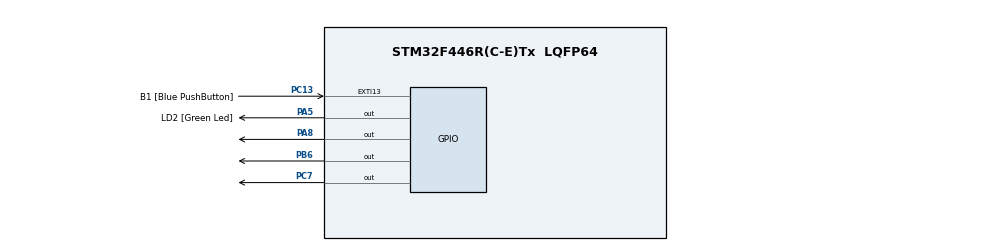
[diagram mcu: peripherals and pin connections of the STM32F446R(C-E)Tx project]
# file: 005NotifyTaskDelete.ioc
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Mcu.Family=STM32F4
Mcu.Name=STM32F446R(C-E)Tx
Mcu.Package=LQFP64
NVIC.PriorityGroup=NVIC_PRIORITYGROUP_4
NVIC.TIM5_IRQn=true\:0\:0\:false\:false\:true\:false\:true
NVIC.TimeBase=TIM5_IRQn
NVIC.TimeBaseIP=TIM5
PA13.GPIO_Label=TMS
PA13.Signal=SYS_JTMS-SWDIO
PA14.GPIO_Label=TCK
PA14.Signal=SYS_JTCK-SWCLK
PA2.GPIO_Label=USART_TX
PA2.Signal=USART2_TX
PA3.GPIO_Label=USART_RX
PA3.Signal=USART2_RX
PA5.GPIO_Label=LD2 [Green Led]
PA5.Signal=GPIO_Output
PA8.Signal=GPIO_Output
PB3.GPIO_Label=SWO
PB3.Signal=SYS_JTDO-SWO
PB6.Signal=GPIO_Output
PC13.GPIO_Label=B1 [Blue PushButton]
PC13.GPIO_ModeDefaultEXTI=GPIO_MODE_IT_FALLING
PC13.Signal=GPXTI13
PC14-OSC32_IN.Signal=RCC_OSC32_IN
PC15-OSC32_OUT.Signal=RCC_OSC32_OUT
PC7.Signal=GPIO_Output
PH0-OSC_IN.Signal=RCC_OSC_IN
PH1-OSC_OUT.Signal=RCC_OSC_OUT
ProjectManager.HeapSize=0x200
ProjectManager.StackSize=0x400
ProjectManager.TargetToolchain=STM32CubeIDE
RCC.AHBFreq_Value=84000000
RCC.APB1CLKDivider=RCC_HCLK_DIV2
RCC.APB1Freq_Value=42000000
RCC.APB1TimFreq_Value=84000000
RCC.APB2Freq_Value=84000000
RCC.APB2TimFreq_Value=84000000
RCC.CortexFreq_Value=84000000
RCC.FLatency-AdvancedSettings=FLASH_LATENCY_2
RCC.HCLKFreq_Value=84000000
RCC.HSE_VALUE=8000000
RCC.HSI_VALUE=16000000
RCC.LSE_VALUE=32768
RCC.PLLN=336
RCC.PLLP=RCC_PLLP_DIV4
RCC.SYSCLKFreq_VALUE=84000000
RCC.SYSCLKSource=RCC_SYSCLKSOURCE_PLLCLK
RCC.USBFreq_Value=168000000
RCC.VCOOutputFreq_Value=336000000
VP_SYS_VS_tim5.Mode=TIM5
board=NUCLEO-F446RE

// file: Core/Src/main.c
/* USER CODE BEGIN Header */
/**
  ******************************************************************************
  * @file           : main.c
  * @brief          : Main program body
  ******************************************************************************
  * @attention
  *
  * <h2><center>&copy; Copyright (c) 2022 STMicroelectronics.
  * All rights reserved.</center></h2>
  *
  * This software component is licensed by ST under BSD 3-Clause license,
  * the "License"; You may not use this file except in compliance with the
  * License. You may obtain a copy of the License at:
  *                        opensource.org/licenses/BSD-3-Clause
  *
  ******************************************************************************
  */
/* USER CODE END Header */

#include "main.h"

/* USER CODE BEGIN Includes */
#include "FreeRTOS.h"
#include "task.h"
/* USER CODE END Includes */

/* USER CODE BEGIN PV */
#define DWT_CTRL (*(volatile uint32_t*)0xE0001000)
/* USER CODE END PV */

void SystemClock_Config(void);
static void MX_GPIO_Init(void);
/* USER CODE BEGIN PFP */
void LedRedTask(void *parameter);
void LedGreenTask(void *parameter);
void LedYellowTask(void *parameter);
static void ButtonTask(void *parameter);
extern void SEGGER_UART_init(U32 baud);
/* USER CODE END PFP */

/* USER CODE BEGIN 0 */
TaskHandle_t GreenTaskHandle;
TaskHandle_t RedTaskHandle;
TaskHandle_t YellowTaskHandle;
TaskHandle_t ButtonTaskHandle;
TaskHandle_t volatile Next_Task_Handle = NULL;
BaseType_t status;
/* USER CODE END 0 */

int main(void)
{

  /* MCU Configuration--------------------------------------------------------*/

  /* Reset of all peripherals, Initializes the Flash interface and the Systick. */
  HAL_Init();

  /* Configure the system clock */
  SystemClock_Config();

  /* Initialize all configured peripherals */
  MX_GPIO_Init();

  //To Start the Sysview recording we have to Call these
  SEGGER_UART_init(250000);//UART

  /* USER CODE BEGIN 2 */
  DWT_CTRL |= (1<<0); //Set the zeroth bit to one //SEGGER UART

  SEGGER_SYSVIEW_Conf();
//  SEGGER_SYSVIEW_Start(); //Already done in UART

  status = xTaskCreate( LedGreenTask, "Led_Green_Task", 200, NULL , 2, &GreenTaskHandle );
  configASSERT(status == pdPASS);

  Next_Task_Handle = GreenTaskHandle;

  status = xTaskCreate( LedRedTask, "Led_Red_Task", 200, NULL , 2, &RedTaskHandle );
  configASSERT(status == pdPASS);
  status = xTaskCreate( LedYellowTask, "Led_Yellow_Task", 200, NULL , 2, &YellowTaskHandle );
  configASSERT(status == pdPASS);
  status = xTaskCreate( ButtonTask, "Button_Task", 200, NULL , 2, &ButtonTaskHandle );
  configASSERT(status == pdPASS);
  /* USER CODE END 2 */

  /* Infinite loop */
  /* USER CODE BEGIN WHILE */
  vTaskStartScheduler();
  while (1)
  {
    /* USER CODE END WHILE */

  }
}

void SystemClock_Config(void)
{
  RCC_OscInitTypeDef RCC_OscInitStruct = {0};
  RCC_ClkInitTypeDef RCC_ClkInitStruct = {0};

  /** Configure the main internal regulator output voltage
  */
  __HAL_RCC_PWR_CLK_ENABLE();
  __HAL_PWR_VOLTAGESCALING_CONFIG(PWR_REGULATOR_VOLTAGE_SCALE1);
  /** Initializes the CPU, AHB and APB busses clocks
  */
  RCC_OscInitStruct.OscillatorType = RCC_OSCILLATORTYPE_HSI;
  RCC_OscInitStruct.HSIState = RCC_HSI_ON;
  RCC_OscInitStruct.HSICalibrationValue = RCC_HSICALIBRATION_DEFAULT;
  RCC_OscInitStruct.PLL.PLLState = RCC_PLL_ON;
  RCC_OscInitStruct.PLL.PLLSource = RCC_PLLSOURCE_HSI;
  RCC_OscInitStruct.PLL.PLLM = 8;
  RCC_OscInitStruct.PLL.PLLN = 168;
  RCC_OscInitStruct.PLL.PLLP = RCC_PLLP_DIV2;
  RCC_OscInitStruct.PLL.PLLQ = 2;
  RCC_OscInitStruct.PLL.PLLR = 2;
  if (HAL_RCC_OscConfig(&RCC_OscInitStruct) != HAL_OK)
  {
    Error_Handler();
  }
  /** Initializes the CPU, AHB and APB busses clocks
  */
  RCC_ClkInitStruct.ClockType = RCC_CLOCKTYPE_HCLK|RCC_CLOCKTYPE_SYSCLK
                              |RCC_CLOCKTYPE_PCLK1|RCC_CLOCKTYPE_PCLK2;
  RCC_ClkInitStruct.SYSCLKSource = RCC_SYSCLKSOURCE_PLLCLK;
  RCC_ClkInitStruct.AHBCLKDivider = RCC_SYSCLK_DIV1;
  RCC_ClkInitStruct.APB1CLKDivider = RCC_HCLK_DIV4;
  RCC_ClkInitStruct.APB2CLKDivider = RCC_HCLK_DIV2;

  if (HAL_RCC_ClockConfig(&RCC_ClkInitStruct, FLASH_LATENCY_5) != HAL_OK)
  {
    Error_Handler();
  }
}

static void MX_GPIO_Init(void)
{
  GPIO_InitTypeDef GPIO_InitStruct = {0};

  /* GPIO Ports Clock Enable */
  __HAL_RCC_GPIOC_CLK_ENABLE();
  __HAL_RCC_GPIOH_CLK_ENABLE();
  __HAL_RCC_GPIOA_CLK_ENABLE();
  __HAL_RCC_GPIOB_CLK_ENABLE();

  /*Configure GPIO pin Output Level */
  HAL_GPIO_WritePin(GPIOA, LD2_Pin|GPIO_PIN_9, GPIO_PIN_RESET);

  /*Configure GPIO pin Output Level */
  HAL_GPIO_WritePin(GPIOC, GPIO_PIN_7, GPIO_PIN_RESET);

  /*Configure GPIO pin Output Level */
  HAL_GPIO_WritePin(GPIOB, GPIO_PIN_6, GPIO_PIN_RESET);

  /*Configure GPIO pin : B1_Pin */
  GPIO_InitStruct.Pin = B1_Pin;
  GPIO_InitStruct.Mode = GPIO_MODE_IT_FALLING;
  GPIO_InitStruct.Pull = GPIO_NOPULL;
  HAL_GPIO_Init(B1_GPIO_Port, &GPIO_InitStruct);

  /*Configure GPIO pins : USART_TX_Pin USART_RX_Pin */
  GPIO_InitStruct.Pin = USART_TX_Pin|USART_RX_Pin;
  GPIO_InitStruct.Mode = GPIO_MODE_AF_PP;
  GPIO_InitStruct.Pull = GPIO_NOPULL;
  GPIO_InitStruct.Speed = GPIO_SPEED_FREQ_VERY_HIGH;
  GPIO_InitStruct.Alternate = GPIO_AF7_USART2;
  HAL_GPIO_Init(GPIOA, &GPIO_InitStruct);

  /*Configure GPIO pins : LD2_Pin PA9 */
  GPIO_InitStruct.Pin = LD2_Pin|GPIO_PIN_9;
  GPIO_InitStruct.Mode = GPIO_MODE_OUTPUT_PP;
  GPIO_InitStruct.Pull = GPIO_NOPULL;
  GPIO_InitStruct.Speed = GPIO_SPEED_FREQ_LOW;
  HAL_GPIO_Init(GPIOA, &GPIO_InitStruct);

  /*Configure GPIO pin : PC7 */
  GPIO_InitStruct.Pin = GPIO_PIN_7;
  GPIO_InitStruct.Mode = GPIO_MODE_OUTPUT_PP;
  GPIO_InitStruct.Pull = GPIO_NOPULL;
  GPIO_InitStruct.Speed = GPIO_SPEED_FREQ_LOW;
  HAL_GPIO_Init(GPIOC, &GPIO_InitStruct);

  /*Configure GPIO pin : PB6 */
  GPIO_InitStruct.Pin = GPIO_PIN_6;
  GPIO_InitStruct.Mode = GPIO_MODE_OUTPUT_PP;
  GPIO_InitStruct.Pull = GPIO_NOPULL;
  GPIO_InitStruct.Speed = GPIO_SPEED_FREQ_LOW;
  HAL_GPIO_Init(GPIOB, &GPIO_InitStruct);

}

/* USER CODE BEGIN 4 */
void LedGreenTask(void *parameter){
	TickType_t last_wakeup_time;
	BaseType_t NotifyTaskStatus;
	last_wakeup_time = xTaskGetTickCount();
	while(1){
		SEGGER_SYSVIEW_PrintfTarget("GREEN LED Task");
		HAL_GPIO_TogglePin(GPIOA, GPIO_PIN_9); //D8 or PA9
		NotifyTaskStatus = xTaskNotifyWait(0,0,NULL,pdMS_TO_TICKS(1000));
		if(NotifyTaskStatus == pdTRUE)
		{
			vTaskSuspendAll();
			Next_Task_Handle = YellowTaskHandle;
			xTaskResumeAll();
			HAL_GPIO_WritePin(GPIOA,GPIO_PIN_9,1);
			vTaskDelete(NULL); //Self-Delete
		}
		else
		{
			//Do Nothing
		}

	}/*End of Infinite Loop*/
}

void LedRedTask(void *parameter){
	TickType_t last_wakeup_time;
	BaseType_t NotifyTaskStatus;
	last_wakeup_time = xTaskGetTickCount();
	while(1){
		SEGGER_SYSVIEW_PrintfTarget("RED LED Task");
		HAL_GPIO_TogglePin(GPIOB, GPIO_PIN_6); //D10 or PB6
		NotifyTaskStatus = xTaskNotifyWait(0,0,NULL,pdMS_TO_TICKS(1000));
		if(NotifyTaskStatus == pdTRUE)
		{
			vTaskSuspendAll();
			Next_Task_Handle = NULL;
			xTaskResumeAll();
			HAL_GPIO_WritePin(GPIOB,GPIO_PIN_6,1);
			vTaskDelete(ButtonTaskHandle);
			vTaskDelete(NULL); //Self-Delete

		}
		else
		{
			//Do Nothing
		}
	}/*End of Infinite Loop*/
}

void LedYellowTask(void *parameter){
	TickType_t last_wakeup_time;
	BaseType_t NotifyTaskStatus;
	last_wakeup_time = xTaskGetTickCount();
	while(1){
		SEGGER_SYSVIEW_PrintfTarget("YELLOW LED Task");
		HAL_GPIO_TogglePin(GPIOC, GPIO_PIN_7); //D9 or PC7
		NotifyTaskStatus = xTaskNotifyWait(0,0,NULL,pdMS_TO_TICKS(1000));
		if(NotifyTaskStatus == pdTRUE)
		{
			vTaskSuspendAll();
			Next_Task_Handle = RedTaskHandle;
			xTaskResumeAll();
			HAL_GPIO_WritePin(GPIOC,GPIO_PIN_7,1);
			vTaskDelete(NULL); //Self-Delete
		}
		else
		{
			//Do Nothing
		}
	}/*End of Infinite Loop*/
}

void ButtonTask(void *parameter){
	uint8_t currentState = 1;
	uint8_t prevState = 1;
	while(1){
		currentState = HAL_GPIO_ReadPin(GPIOC, GPIO_PIN_13);
		if (currentState == GPIO_PIN_RESET)
		{
			if(prevState)
			{
				xTaskNotify(Next_Task_Handle,0,eNoAction);
			}

		}
		prevState = currentState;
		vTaskDelay(pdMS_TO_TICKS(10));
	}/*End of Infinite Loop*/
}

/* USER CODE END 4 */

 /**
  * @brief  Period elapsed callback in non blocking mode
  * @note   This function is called  when TIM5 interrupt took place, inside
  * HAL_TIM_IRQHandler(). It makes a direct call to HAL_IncTick() to increment
  * a global variable "uwTick" used as application time base.
  * @param  htim : TIM handle
  * @retval None
  */
void HAL_TIM_PeriodElapsedCallback(TIM_HandleTypeDef *htim)
{
  if (htim->Instance == TIM5) {
    HAL_IncTick();
  }
}

void Error_Handler(void)
{
}

/************************ (C) COPYRIGHT STMicroelectronics *****END OF FILE****/
